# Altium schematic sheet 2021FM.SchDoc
size A4

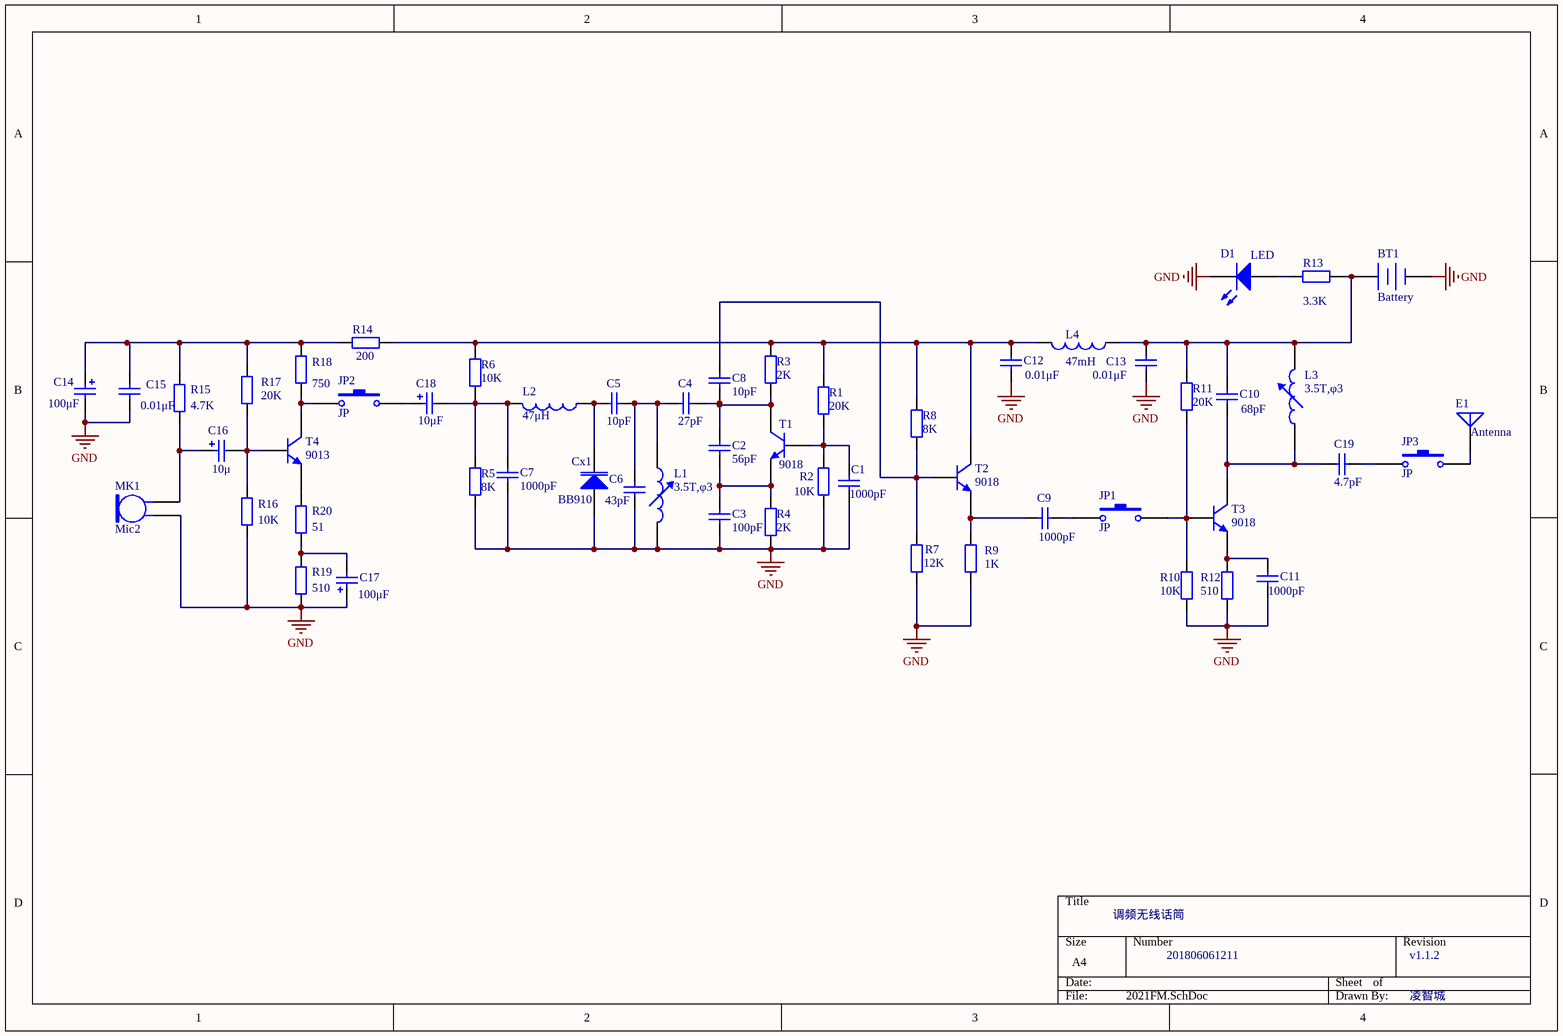
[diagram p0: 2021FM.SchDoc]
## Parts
BT1  Battery  [BAT-2]
C1  value 1000pF  [CAP]  (hidden comment: Cap)
C2  value 56pF  [CAP]  (hidden comment: Cap)
C3  value 100pF  [CAP]  (hidden comment: Cap)
C4  value 27pF  [CAP]  (hidden comment: Cap)
C5  value 10pF  [CAP]  (hidden comment: Cap)
C6  value 43pF  [CAP]  (hidden comment: Cap)
C7  value 1000pF  [CAP]  (hidden comment: Cap)
C8  value 10pF  [CAP]  (hidden comment: Cap)
C9  value 1000pF  [CAP]  (hidden comment: Cap)
C10  value 68pF  [CAP]  (hidden comment: Cap)
C11  value 1000pF  [CAP]  (hidden comment: Cap)
C12  value 0.01μF  [CAP]  (hidden comment: Cap)
C13  value 0.01μF  [CAP]  (hidden comment: Cap)
C14  value 100μF  [CAP POL 100μF]  (hidden comment: Cap Pol2)
C15  value 0.01μF  [CAP]  (hidden comment: Cap)
C16  value 10μ  [CAP POL 10μF]  (hidden comment: Cap Pol2)
C17  value 100μF  [CAP POL 100μF]  (hidden comment: Cap Pol2)
C18  value 10μF  [CAP POL 10μF]  (hidden comment: Cap Pol2)
C19  value 4.7pF  [CAP]  (hidden comment: Cap)
Cx1  BB910  [D VACTOR]
D1  LED  [LED]
E1  Antenna  [PIN1]
JP1  JP  [Jumper]
JP2  JP  [Jumper]
JP3  JP  [Jumper]
L1  value 3.5T,φ3  [ADJ]  (hidden comment: Inductor Adj)
L2  value 47μH  [INDUCTOR]  (hidden comment: Inductor)
L3  value 3.5T,φ3  [ADJ]  (hidden comment: Inductor Adj)
L4  value 47mH  [INDUCTOR]  (hidden comment: Inductor)
MK1  Mic2  [Microphone]
R1  value 20K  [RES]  (hidden comment: Res2)
R2  value 10K  [RES]  (hidden comment: Res2)
R3  value 2K  [RES]  (hidden comment: Res2)
R4  value 2K  [RES]  (hidden comment: Res2)
R5  value 8K  [RES]  (hidden comment: Res2)
R6  value 10K  [RES]  (hidden comment: Res2)
R7  value 12K  [RES]  (hidden comment: Res2)
R8  value 8K  [RES]  (hidden comment: Res2)
R9  value 1K  [RES]  (hidden comment: Res2)
R10  value 10K  [RES]  (hidden comment: Res2)
R11  value 20K  [RES]  (hidden comment: Res2)
R12  value 510  [RES]  (hidden comment: Res2)
R13  value 3.3K  [RES]  (hidden comment: Res2)
R14  value 200  [RES]  (hidden comment: Res2)
R15  value 4.7K  [RES]  (hidden comment: Res2)
R16  value 10K  [RES]  (hidden comment: Res2)
R17  value 20K  [RES]  (hidden comment: Res2)
R18  value 750  [RES]  (hidden comment: Res2)
R19  value 510  [RES]  (hidden comment: Res2)
R20  value 51  [RES]  (hidden comment: Res2)
T1  9018  [three]
T2  9018  [three]
T3  9018  [three]
T4  9013  [three]

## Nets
GND: BT1.2(-) C1.1 C3.1 C6.1 C7.1 C11.1 C12.1 C13.1 C14.2 C15.1 C17.1 Cx1.2(A) D1.2(K) L1.1 MK1.1 R2.1 R4.1 R5.1 R7.1 R9.2 R10.1 R12.1 R16.1 R19.1
NetBT1_1: BT1.1(+) C10.2 C13.2 L3.2 L4.1 R11.2 R13.2
NetC1_2: C1.2 R1.1 R2.2 T1.2(B)
NetC2_1: C2.1 C3.2 R4.2 T1.3(E)
NetC2_2: C2.2 C4.1 C8.2 R3.1 T1.1(C)
NetC4_2: C4.2 C5.2 C6.2 L1.2
NetC5_1: C5.1 Cx1.1(K) L2.2
NetC7_2: C7.2 C18.2 L2.1 R5.2 R6.1
NetC8_1: C8.1 R7.2 R8.2 T2.2(B)
NetC9_1: C9.1 JP1.1
NetC9_2: C9.2 R9.1 T2.3(E)
NetC10_1: C10.1 C19.2 L3.1 T3.1(C)
NetC11_2: C11.2 R12.2 T3.3(E)
NetC12_2: C12.2 L4.2 R1.2 R3.2 R6.2 R8.1 R14.2 T2.1(C)
NetC14_1: C14.1 C15.2 R14.1 R15.2 R17.2 R18.2
NetC16_1: C16.1 MK1.2 R15.1
NetC16_2: C16.2 R16.2 R17.1 T4.2(B)
NetC17_2: C17.2 R19.2 R20.1
NetC18_1: C18.1 JP2.2
NetC19_1: C19.1 JP3.1
NetD1_1: D1.1(A) R13.1
NetE1_1: E1.1(A) JP3.2
NetJP1_2: JP1.2 R10.2 R11.1 T3.2(B)
NetJP2_1: JP2.1 R18.1 T4.1(C)
NetR20_2: R20.2 T4.3(E)

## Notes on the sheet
- 调频无线话筒
- 201806061211
- v1.1.2
- 凌智城

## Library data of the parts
BT1 = Battery: Multicell Battery
C1-C13 C15 C19 = Cap: Capacitor
C14 C16-C18 = Cap Pol2: Polarized Capacitor (Axial)
Cx1 = D Varactor: Variable Capacitance Diode; Note: Pin 2 is not connected and not drawn.
D1 = LED0: Typical INFRARED GaAs LED
E1 = Antenna: Generic Antenna
JP1-JP3 = SW-PB: Switch
L1 L3 = Inductor Adj: Adjustable Inductor; Set Position: 0.5
L2 L4 = Inductor: Code_IEC: 1005
MK1 = Mic2: Microphone
R1-R20 = Res2: Resistor
T1-T4 = NPN: NPN Bipolar Transistor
